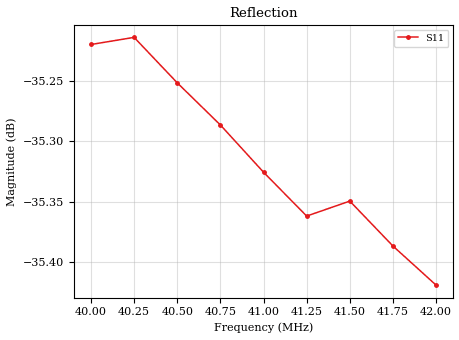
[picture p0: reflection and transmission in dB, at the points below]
# Hz S RI R 50
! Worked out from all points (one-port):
!   9 points, 40 MHz to 42 MHz, reference 50 ohm
!   lowest |S11| = -35.4 dB at 42 MHz (marker M1), VSWR 1.03, Z = 50.7 - j1.56 ohm
!   |S11| at or under -10 dB: start of sweep to end of sweep
4e7  0.00834 -0.0152
4.025e7  0.00818 -0.0153
4.05e7  0.00802 -0.0153
4.075e7  0.00787 -0.0153
4.1e7  0.0077 -0.0153
4.125e7  0.00754 -0.0153
4.15e7  0.00739 -0.0154
4.175e7  0.00722 -0.0154
4.2e7  0.00707 -0.0154
